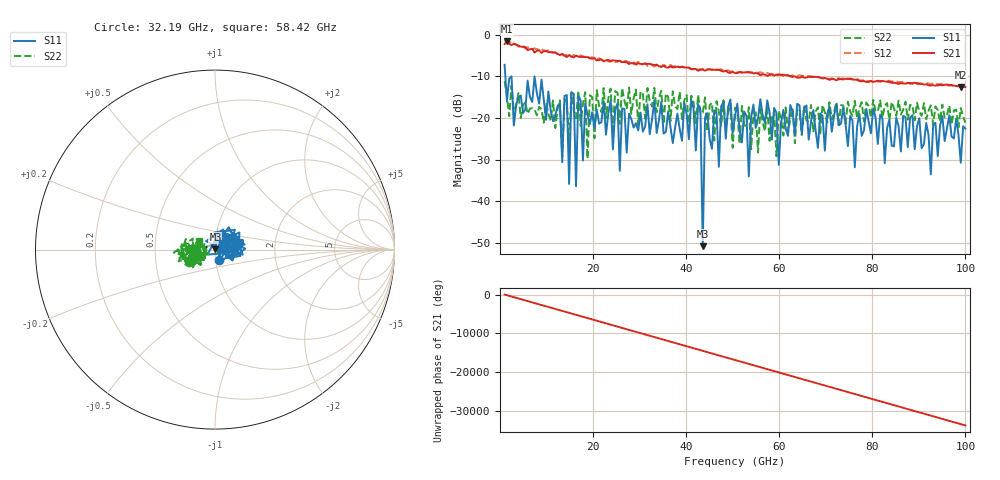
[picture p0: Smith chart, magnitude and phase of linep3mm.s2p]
!Created with skrf (http://scikit-rf.org).
# GHz S RI R 50.0
!freq ReS11 ImS11 ReS21 ImS21 ReS12 ImS12 ReS22 ImS22
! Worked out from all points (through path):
!   201 points, 1 GHz to 100 GHz, reference 50 ohm
!   highest |S21| = -1.51 dB at 1.495 GHz (marker M1); lowest = -12.5 dB at 99.01 GHz (marker M2)
!   lowest |S11| = -50.8 dB at 43.57 GHz (marker M3), VSWR 1.01, Z = 50.3 + j0.134 ohm
!   |S11| at or under -10 dB: 1.159 GHz to 2.447 GHz (1.288 GHz wide, 71.5 % of centre); 2.487 GHz to 7.434 GHz (4.947 GHz wide, 99.7 % of centre); 7.437 GHz to end of sweep
!   |S22| runs from -29.7 to -11.2 dB; largest |S21 - S12| = 0.11
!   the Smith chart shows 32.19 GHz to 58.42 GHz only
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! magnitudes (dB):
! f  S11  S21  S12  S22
! 1 GHz  -7.2  -2.2  -1.3  -11.2
! 1.495 GHz  -15.9  -1.5  -1.5  -14.7
! 8.92 GHz  -10.7  -4.3  -3.4  -17.9
! 13.38 GHz  -30.6  -4.6  -4.6  -29.3
! 14.37 GHz  -14.5  -5.3  -4.8  -16.4
! 14.86 GHz  -35.8  -4.8  -4.9  -26.3
! 15.85 GHz  -14.2  -5.4  -4.9  -18.1
! 16.34 GHz  -36.4  -5.0  -5.1  -20.0
! 16.84 GHz  -14.6  -5.3  -5.3  -13.5
! 17.83 GHz  -30.2  -5.2  -5.3  -16.6
! 34.16 GHz  -20.4  -7.5  -7.4  -15.2
! 43.08 GHz  -18.0  -8.4  -8.3  -18.9
! 43.57 GHz  -50.8  -8.4  -8.2  -18.7
! 44.06 GHz  -19.8  -8.6  -8.4  -15.0
! 50.5 GHz  -19.6  -9.2  -8.8  -17.5
! 53.47 GHz  -34.0  -8.9  -9.0  -17.4
! 54.46 GHz  -16.8  -9.3  -9.0  -19.0
! 59.91 GHz  -31.2  -9.5  -9.6  -18.2
! 67.33 GHz  -18.1  -10.1  -10.0  -23.4
! 83.67 GHz  -20.4  -11.3  -11.0  -20.5
! 99.01 GHz  -30.7  -12.5  -12.3  -17.6
! 100 GHz  -22.5  -12.5  -12.3  -21.1
